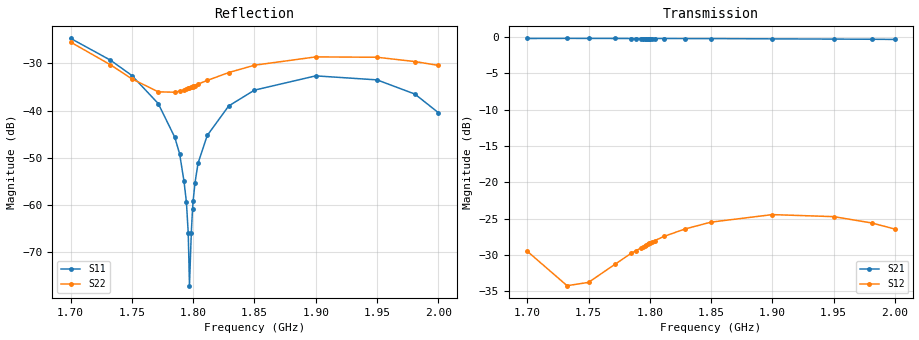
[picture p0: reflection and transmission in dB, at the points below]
! MS46524B
! 12345/M1: Not Set/M2: Not Set
! 3/11/2021 8:31:21 PM
! D:\WEBSITE FILES\DATASHEETS\MEASURED DATA\1.7-2.0 GHZ (D4I0120).S2P
! CHANNEL.1
! TR.MEASUREMENT
! RAW.DATA
# GHZ S RI R 50.0
! FREQ.GHZ  S11RE  S11IM  S21RE  S21IM  S12RE  S12IM  S22RE  S22IM
!; PortSelection: Port_12
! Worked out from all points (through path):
!   601 points, 1.7 GHz to 2 GHz, reference 50 ohm
!   highest |S21| = -0.16 dB at 1.732 GHz (marker M1); lowest = -0.3 dB at 2 GHz (marker M2)
!   lowest |S11| = -77.2 dB at 1.797 GHz (marker M3), VSWR 1.00, Z = 50 - j0.0135 ohm
!   |S11| at or under -10 dB: start of sweep to end of sweep
!   |S22| runs from -36.4 to -25.5 dB; largest |S21 - S12| = 1
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1.7  0.044 -0.0382  0.3885 0.8997  0.0241 -0.0232  0.048 -0.023
1.7325  0.0239 -0.0245  0.5209 0.8325  -0.00317 -0.0191  0.0292 -0.00904
1.75  0.0156 -0.0176  0.5859 0.7873  -0.0153 -0.0135  0.0216 -0.00188
1.7715  0.00741 -0.00925  0.6601 0.7248  -0.0268 -0.00447  0.0144 0.00647
1.785  0.00307 -0.0042  0.7029 0.6826  -0.0324 0.00202  0.0108 0.0113
1.789  0.00195 -0.00285  0.715 0.67  -0.0336 0.00404  0.00989 0.0126
1.7925  0.00103 -0.00146  0.7254 0.6585  -0.0347 0.00569  0.00907 0.0138
1.7945  0.00056 -0.000912  0.7312 0.6519  -0.0354 0.00675  0.00865 0.0146
1.796  0.000195 -0.000459  0.7356 0.647  -0.0358 0.00757  0.0084 0.0151
1.797  3.07e-05 -0.000135  0.7383 0.6437  -0.0361 0.00815  0.0082 0.0153
1.7985  -0.000327 0.000386  0.7428 0.6387  -0.0365 0.00893  0.00793 0.0159
1.7995  -0.000578 0.000688  0.7458 0.6353  -0.0368 0.00941  0.00778 0.0162
1.8  -0.00072 0.000838  0.747 0.6334  -0.0369 0.0097  0.00763 0.0164
1.8015  -0.00105 0.00134  0.7514 0.6281  -0.0373 0.0104  0.00743 0.0168
1.804  -0.00157 0.00227  0.7584 0.6197  -0.0378 0.0117  0.00711 0.0177
1.8115  -0.00293 0.00458  0.7793 0.5933  -0.0393 0.0157  0.00592 0.02
1.829  -0.00567 0.00963  0.8238 0.529  -0.0409 0.0246  0.0043 0.0249
1.85  -0.00737 0.0147  0.8709 0.4463  -0.0402 0.0347  0.00366 0.03
1.9  -0.00646 0.0224  0.9459 0.2343  -0.0298 0.0519  0.00745 0.0363
1.95  -0.00125 0.0211  0.9707 0.00916  -0.0141 0.0562  0.0155 0.0333
1.981  0.00258 0.0147  0.9588 -0.1336  -0.00584 0.0521  0.0209 0.0256
2  0.00446 0.00838  0.9401 -0.2205  -0.00235 0.0475  0.0237 0.0186
